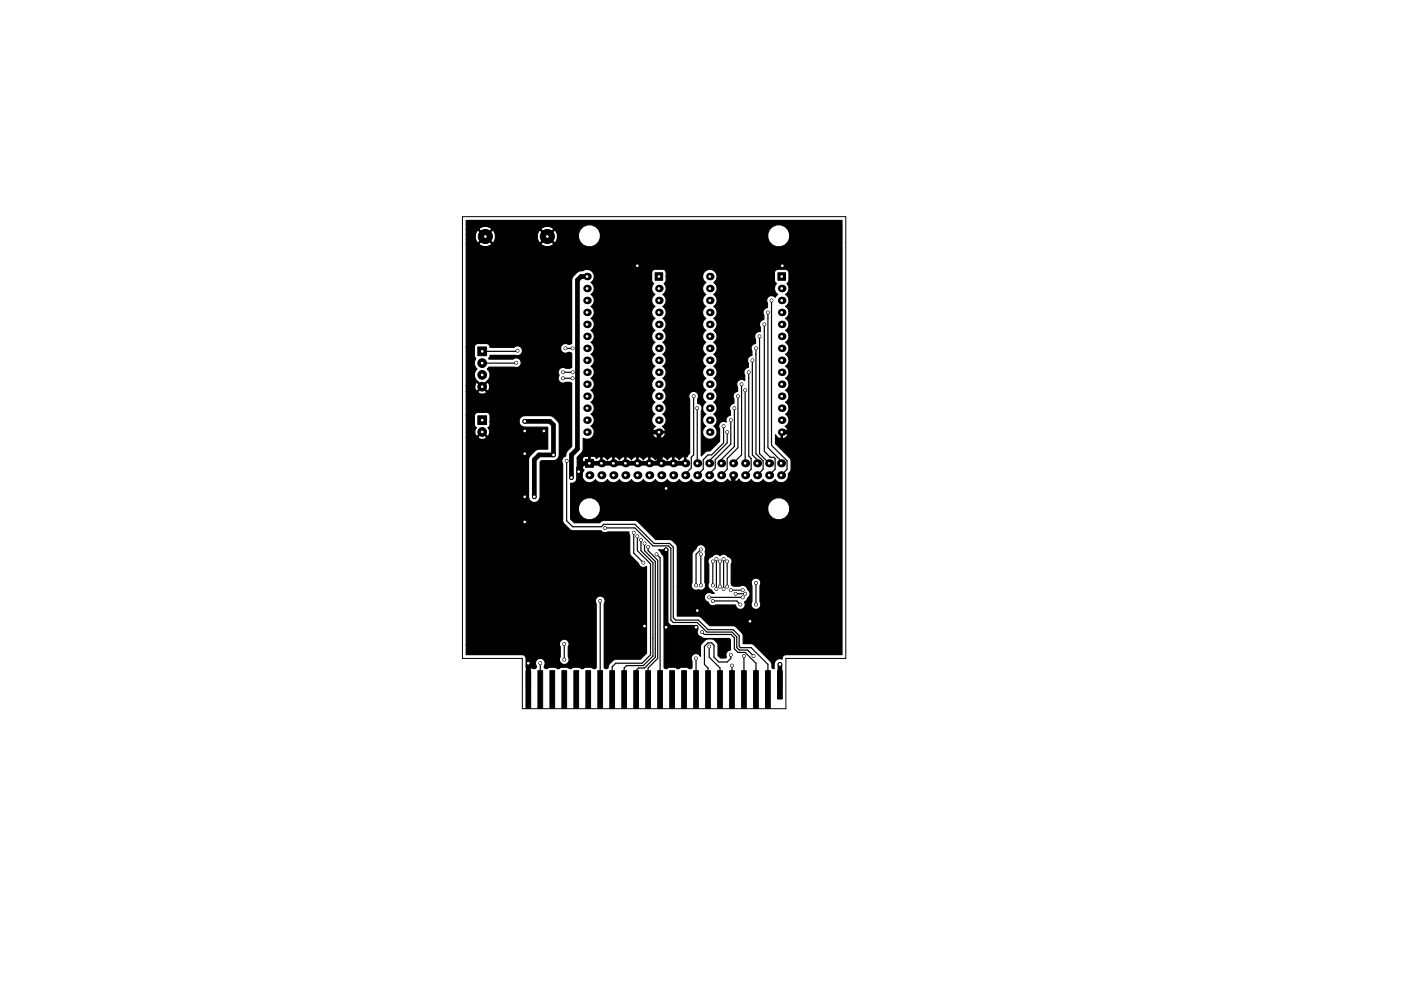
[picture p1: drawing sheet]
<svg xmlns="http://www.w3.org/2000/svg" width="297mm" height="210mm" viewBox="0 0 297 210" stroke-linecap="round" stroke-linejoin="round" font-family="sans-serif">
<path d="M98 46h81.3v93.7h-12.7v10.7h-55.9v-10.7h-12.7z" fill="none" stroke="#000" stroke-width=".21"/>
<g fill="#000" stroke="#000" stroke-width=".21">
<path d="M138.9 57.9h1.6v1.6h-1.6zM164.9 57.9h1.6v1.6h-1.6zM101.3 73.6h1.9v1.9h-1.9zM101.3 88.2h1.9v1.9h-1.9zM124.1 97.4h1.7v1.7h-1.7zM111.5 142.3h1v8h-1zM114.1 142.3h1v8h-1zM116.6 142.3h1v8h-1zM119.1 142.3h1v8h-1zM121.7 142.3h1v8h-1zM124.2 142.3h1v8h-1zM126.8 142.3h1v8h-1z"/>
<path d="M129.3 142.3h1v8h-1zM131.8 142.3h1v8h-1zM134.4 142.3h1v8h-1zM136.9 142.3h1v8h-1zM139.5 142.3h1v8h-1zM142 142.3h1v8h-1zM144.5 142.3h1v8h-1zM147.1 142.3h1v8h-1zM149.6 142.3h1v8h-1zM152.2 142.3h1v8h-1zM154.7 142.3h1v8h-1zM157.2 142.3h1v8h-1z"/>
<path d="M159.8 142.3h1v8h-1zM162.3 142.3h1v8h-1zM164.9 142.3h1v6h-1z"/>
<circle cx="102.9" cy="50.2" r="1.5"/>
<circle cx="116" cy="50.2" r="1.5"/>
<circle cx="135.1" cy="56.4" r=".4"/>
<circle cx="165.9" cy="56.4" r=".4"/>
<circle cx="102.2" cy="77" r=".92"/>
<circle cx="102.2" cy="79.5" r=".92"/>
<circle cx="109.5" cy="77" r=".3"/>
<circle cx="109.7" cy="74.4" r=".3"/>
<circle cx="119.4" cy="79" r=".3"/>
<circle cx="119.9" cy="73.9" r=".3"/>
<circle cx="121.4" cy="73.9" r=".3"/>
<circle cx="121.4" cy="79" r=".3"/>
<circle cx="158.8" cy="79" r=".3"/>
<circle cx="159.5" cy="76.4" r=".3"/>
<circle cx="160.3" cy="73.9" r=".3"/>
<circle cx="161" cy="71.4" r=".3"/>
<circle cx="162.1" cy="68.8" r=".3"/>
<circle cx="162.8" cy="66.3" r=".3"/>
<circle cx="163.6" cy="63.7" r=".3"/>
<circle cx="102.2" cy="91.6" r=".92"/>
<circle cx="102.2" cy="82" r=".92"/>
<circle cx="111.3" cy="96.3" r=".4"/>
<circle cx="111.3" cy="89.4" r=".4"/>
<circle cx="111.3" cy="91.4" r=".4"/>
<circle cx="115.3" cy="91.4" r=".4"/>
<circle cx="117.3" cy="96.5" r=".4"/>
<circle cx="119.4" cy="80.3" r=".3"/>
<circle cx="120.1" cy="97.8" r=".3"/>
<circle cx="121.4" cy="80.3" r=".3"/>
<circle cx="147.1" cy="84.1" r=".3"/>
<circle cx="147.8" cy="86.6" r=".3"/>
<circle cx="153.4" cy="90.4" r=".3"/>
<circle cx="154.2" cy="91.7" r=".3"/>
<circle cx="154.9" cy="89.1" r=".3"/>
<circle cx="155.7" cy="86.6" r=".3"/>
<circle cx="156.5" cy="84.1" r=".3"/>
<circle cx="157.2" cy="81.5" r=".3"/>
<circle cx="158" cy="82.8" r=".3"/>
<circle cx="111.3" cy="110.7" r=".4"/>
<circle cx="111.3" cy="105.4" r=".4"/>
<circle cx="113.3" cy="105.4" r=".4"/>
<circle cx="121.2" cy="101.3" r=".4"/>
<circle cx="122.7" cy="100.1" r=".4"/>
<circle cx="128.3" cy="112" r=".3"/>
<circle cx="134.4" cy="113" r=".3"/>
<circle cx="135.1" cy="113.8" r=".3"/>
<circle cx="135.9" cy="114.5" r=".3"/>
<circle cx="136.4" cy="119.4" r=".3"/>
<circle cx="136.7" cy="115.3" r=".3"/>
<circle cx="137.4" cy="116.1" r=".3"/>
<circle cx="139.2" cy="117.6" r=".3"/>
<circle cx="141.2" cy="103.6" r=".4"/>
<circle cx="141.2" cy="116.6" r=".4"/>
<circle cx="148.6" cy="116.6" r=".3"/>
<circle cx="148.6" cy="117.6" r=".3"/>
<circle cx="151.1" cy="119.1" r=".3"/>
<circle cx="151.9" cy="118.6" r=".3"/>
<circle cx="152.7" cy="119.1" r=".3"/>
<circle cx="153.4" cy="118.6" r=".3"/>
<circle cx="154.2" cy="119.1" r=".3"/>
<circle cx="119.6" cy="136.6" r=".3"/>
<circle cx="119.6" cy="139.9" r=".3"/>
<circle cx="127.3" cy="127.5" r=".3"/>
<circle cx="136.7" cy="132.8" r=".4"/>
<circle cx="141.2" cy="133.1" r=".4"/>
<circle cx="147.6" cy="133.1" r=".4"/>
<circle cx="147.6" cy="139.7" r=".3"/>
<circle cx="147.6" cy="124.2" r=".3"/>
<circle cx="147.8" cy="129.5" r=".4"/>
<circle cx="148.6" cy="124.2" r=".3"/>
<circle cx="148.8" cy="134.1" r=".3"/>
<circle cx="150.4" cy="137.2" r=".3"/>
<circle cx="150.4" cy="126.7" r=".3"/>
<circle cx="151.1" cy="127.5" r=".3"/>
<circle cx="151.1" cy="124.2" r=".3"/>
<circle cx="151.9" cy="125" r=".3"/>
<circle cx="152.7" cy="124.5" r=".3"/>
<circle cx="153.4" cy="125" r=".3"/>
<circle cx="154.2" cy="124.5" r=".3"/>
<circle cx="154.9" cy="138.9" r=".3"/>
<circle cx="154.9" cy="125.2" r=".3"/>
<circle cx="156" cy="126" r=".3"/>
<circle cx="157" cy="128.3" r=".3"/>
<circle cx="157.5" cy="126.7" r=".3"/>
<circle cx="157.5" cy="125.2" r=".3"/>
<circle cx="157.7" cy="139.2" r=".3"/>
<circle cx="158" cy="126" r=".3"/>
<circle cx="159" cy="131.8" r=".4"/>
<circle cx="159.8" cy="139.2" r=".3"/>
<circle cx="160.3" cy="128.3" r=".3"/>
<circle cx="160.3" cy="123.7" r=".3"/>
<circle cx="112" cy="140.7" r=".4"/>
<circle cx="114.6" cy="140.7" r=".3"/>
<circle cx="155.2" cy="141.2" r=".3"/>
<circle cx="165.4" cy="141" r=".4"/>
</g>
<g fill="#000">
<circle cx="124.5" cy="58.7" r=".8"/>
<circle cx="150.5" cy="58.7" r=".8"/>
<circle cx="124.5" cy="63.7" r=".8"/>
<circle cx="124.5" cy="61.2" r=".8"/>
<circle cx="124.5" cy="76.4" r=".8"/>
<circle cx="124.5" cy="66.3" r=".8"/>
<circle cx="124.5" cy="79" r=".8"/>
<circle cx="124.5" cy="71.4" r=".8"/>
<circle cx="124.5" cy="68.8" r=".8"/>
<circle cx="124.5" cy="73.9" r=".8"/>
<circle cx="139.7" cy="61.2" r=".8"/>
<circle cx="139.7" cy="63.7" r=".8"/>
<circle cx="139.7" cy="68.8" r=".8"/>
<circle cx="139.7" cy="71.4" r=".8"/>
<circle cx="139.7" cy="73.9" r=".8"/>
<circle cx="139.7" cy="76.4" r=".8"/>
<circle cx="139.7" cy="66.3" r=".8"/>
<circle cx="139.7" cy="79" r=".8"/>
<circle cx="150.5" cy="61.2" r=".8"/>
<circle cx="150.5" cy="63.7" r=".8"/>
<circle cx="150.5" cy="79" r=".8"/>
<circle cx="150.5" cy="76.4" r=".8"/>
<circle cx="150.5" cy="68.8" r=".8"/>
<circle cx="150.5" cy="73.9" r=".8"/>
<circle cx="150.5" cy="71.4" r=".8"/>
<circle cx="150.5" cy="66.3" r=".8"/>
<circle cx="165.7" cy="61.2" r=".8"/>
<circle cx="165.7" cy="66.3" r=".8"/>
<circle cx="165.7" cy="71.4" r=".8"/>
<circle cx="165.7" cy="63.7" r=".8"/>
<circle cx="165.7" cy="73.9" r=".8"/>
<circle cx="165.7" cy="76.4" r=".8"/>
<circle cx="165.7" cy="79" r=".8"/>
<circle cx="165.7" cy="68.8" r=".8"/>
<circle cx="124.5" cy="81.5" r=".8"/>
<circle cx="124.5" cy="91.7" r=".8"/>
<circle cx="124.5" cy="89.1" r=".8"/>
<circle cx="124.5" cy="86.6" r=".8"/>
<circle cx="124.5" cy="84.1" r=".8"/>
<circle cx="127.5" cy="98.3" r=".85"/>
<circle cx="130" cy="98.3" r=".85"/>
<circle cx="132.6" cy="98.3" r=".85"/>
<circle cx="135.1" cy="98.3" r=".85"/>
<circle cx="137.7" cy="98.3" r=".85"/>
<circle cx="139.7" cy="84.1" r=".8"/>
<circle cx="139.7" cy="86.6" r=".8"/>
<circle cx="139.7" cy="91.7" r=".8"/>
<circle cx="139.7" cy="89.1" r=".8"/>
<circle cx="139.7" cy="81.5" r=".8"/>
<circle cx="140.2" cy="98.3" r=".85"/>
<circle cx="142.7" cy="98.3" r=".85"/>
<circle cx="145.3" cy="98.3" r=".85"/>
<circle cx="147.8" cy="98.3" r=".85"/>
<circle cx="150.4" cy="98.3" r=".85"/>
<circle cx="150.5" cy="89.1" r=".8"/>
<circle cx="150.5" cy="84.1" r=".8"/>
<circle cx="150.5" cy="81.5" r=".8"/>
<circle cx="150.5" cy="91.7" r=".8"/>
<circle cx="150.5" cy="86.6" r=".8"/>
<circle cx="152.9" cy="98.3" r=".85"/>
<circle cx="155.4" cy="98.3" r=".85"/>
<circle cx="158" cy="98.3" r=".85"/>
<circle cx="160.5" cy="98.3" r=".85"/>
<circle cx="163.1" cy="98.3" r=".85"/>
<circle cx="165.6" cy="98.3" r=".85"/>
<circle cx="165.7" cy="81.5" r=".8"/>
<circle cx="165.7" cy="91.7" r=".8"/>
<circle cx="165.7" cy="84.1" r=".8"/>
<circle cx="165.7" cy="89.1" r=".8"/>
<circle cx="165.7" cy="86.6" r=".8"/>
<circle cx="125" cy="100.8" r=".85"/>
<circle cx="127.5" cy="100.8" r=".85"/>
<circle cx="130" cy="100.8" r=".85"/>
<circle cx="132.6" cy="100.8" r=".85"/>
<circle cx="135.1" cy="100.8" r=".85"/>
<circle cx="137.7" cy="100.8" r=".85"/>
<circle cx="140.2" cy="100.8" r=".85"/>
<circle cx="142.7" cy="100.8" r=".85"/>
<circle cx="145.3" cy="100.8" r=".85"/>
<circle cx="147.8" cy="100.8" r=".85"/>
<circle cx="150.4" cy="100.8" r=".85"/>
<circle cx="152.9" cy="100.8" r=".85"/>
<circle cx="155.4" cy="100.8" r=".85"/>
<circle cx="158" cy="100.8" r=".85"/>
<circle cx="160.5" cy="100.8" r=".85"/>
<circle cx="163.1" cy="100.8" r=".85"/>
<circle cx="165.6" cy="100.8" r=".85"/>
</g>
<path d="M124.5 58.7h-1.3l-.8 .7v35.8l-1.2 1.3v4.8M135.1 56.4v34.8l.5 .5h4.1v6.1l.5 .5M165.9 56.4h10.4l1 1v71.1l-3.3 3.3h-23.9l-2.3-2.3M167.4 56.4l.5 .5v34.3l-.5 .5h-1.7M111.3 89.4h5.3l.7 .8v6.3h-3l-1 1v7.9M115.3 91.4h-4v14M145.3 98.3h-21.6l-1 1v3.1l1.3 1.2h30.9l.5-.5v-2.3M111.3 110.7l.7 .8v34.8M141.2 116.6v16.5h6.4M112 125.2h17l7.7 7.6M165.4 141v4.3" fill="none" stroke="#000" stroke-width="1"/>
<g fill="none" stroke="#000" stroke-width=".25">
<path d="M109.5 77h-7.3M109.7 74.4l-.1 .1h-7.4M119.4 79h2M119.9 73.9h1.5M158.7 79v17.8l.6 .5v2.3l-1.3 1.2M159.5 76.4v20.1l1 1v.8M160.3 73.9v22.4l1.5 1.5v1.8l-1.3 1.2M161 71.4v24.9l2.1 2M162.1 68.8v27l1.2 1.2h.8l.2 .3v2.3l-1.2 1.2M162.8 66.3v28.7l2.8 2.8v.5M163.6 63.7v30.8l3.3 3.3v1.8l-1.3 1.2M119.4 80.3h2"/>
<path d="M120.1 97.8v12.7l1.3 1.3h6.1l.5-.6h6.6l4.1 4.1h3.3l.7 .8v15l.6 .5h4.8l2 2h5.3l1.3 1.3v2.3l.3 .2h2.3l3.5 3.6v5.3M147.1 84.1v12.4l-.5 .5v2.3l-1.3 1.3v.2M147.8 86.6v11.7M153.4 90.4v3.6l-2.5 2.5h-.8l-1 1v2.1l-1.3 1.2M154.2 91.7v2.3l-3.8 3.8v.5M154.9 89.1v5.1l-3.3 3.3v1.8l-1.2 1.3v.2M155.7 86.6v8.1l-2.8 2.8v.8M156.5 84.1v10.9l-2.3 2.3v2.3l-1.3 1.2M157.2 81.5v15l-1.8 1.8M158 82.8v15.5M128.3 112h6.3l3.8 3.8h3.3l.5 .5v15.3l.5 .5h5.1l2.1 2h5.3l1 1v2.3l.5 .5h1.8l1.3 1.3M134.4 113v4.3l2 2.1"/>
<path d="M135.1 113.8v3l2.8 2.8v19.3l-1.8 1.8h-5.5l-.8 .8v4.8l.2-.3M135.9 114.5v2.3l2.5 2.6v19.8l-2 2h-3.6l-.5 .5v4.6M136.7 115.3v1.5l2.2 2.3v20.3l-2.2 2.3h-1.3l-.5 .5v4.1M137.4 116.1v.7l2 2.1v20.8l-2 2v4.6M139.2 117.6l.8 .8v27.9M148.6 117.6v6.6M148.6 116.6l-1 1v6.6M151.1 119.1v5.1M151.9 118.6v6.4M152.7 119.1v5.4M153.4 118.6v6.4M154.2 119.1v5.4"/>
<path d="M119.6 136.6v3.3M127.3 127.5v18.8M147.6 139.7v6.6M148.8 134.1l.6 .5h5.6l.7 .7v2.4l.8 .7h1.5l2.3 2.3v5.6M150.4 137.2v2.2l2.3 2.3v4.6M150.4 126.7h7.1M151.1 127.5h5.1l.8 .8M154.9 138.9v.8l-.7 .8h-1.8l-1-1.1v-2.5l-.5-.5h-.8l-.7 .8v3.8l.7 .7v4.6M154.9 125.2h2.6M156 126h2M157.7 139.2v7.1M160.3 123.7v4.6"/>
<path d="M114.6 140.7v5.6M155.2 141.2v5.1"/>
</g>
<path d="M139.6 116.7h1.8v14.9a1.76 1.76 0 0 0 1.3 1.3h4.8l.5 .6a1.11 1.11 0 0 0 .7 1.7l.7 .3h5.2l.3 .2v2.2a1.01 1.01 0 0 0-.9 1.5l-.2 .2h-1l-.6-.5v-2.2a1.91 1.91 0 0 0-1.9-1.4 1.91 1.91 0 0 0-1.8 1.7v2a1.04 1.04 0 0 0-1.5-.4 1.04 1.04 0 0 0-.3 1.5v1.4l-.2 .2-.4-.1a2 2 0 0 0-2.1 0h-.5a2 2 0 0 0-2 0l-.5 .1-.2-.2v-23.3l-.7-1.4zM98.8 46.8h79.7v92.1l-12.2 .1a.83 .83 0 0 0-.5 .8 1.23 1.23 0 0 0-1.7 1.2v.9h-.2l-.2-.2v-.7l-.3-.6-3.5-3.6-.6-.2h-1.7l-.1-2.1-1.7-1.7-5.3-.1-2.1-1.9-4.8-.1v-3.8h5.7l.2 .4 .6 .4 .2 .4a1.04 1.04 0 0 0 1.4 .3h4.2a1.04 1.04 0 0 0 1.5 .8 1.04 1.04 0 0 0 .4-1.5 .95 .95 0 0 0 .7-.8 1.09 1.09 0 0 0 0-1.9 1.04 1.04 0 0 0-1.6-.6h-1.4l-.3-.2-.1-.3h4.1l.2 .4v3.4a1.04 1.04 0 0 0 .9 1.6 1.04 1.04 0 0 0 .8-1.6v-3.4a1.05 1.05 0 0 0-.6-1.6 1.05 1.05 0 0 0-1.3 1.2h-4.1l-.1-4.2a1.1 1.1 0 0 0-.7-1.7 1.02 1.02 0 0 0-1.6-.1 1.09 1.09 0 0 0-1.8 .2 1.04 1.04 0 0 0-.6 1.6v3.9a1.04 1.04 0 0 0 .6 1.6l.1 .3 .4 .4h-.4a1.04 1.04 0 0 0-1.2 0 1.04 1.04 0 0 0-.5 1h-5.7v-2.5h2.9l.2 .4a1.02 1.02 0 0 0 1.4 .3 1.04 1.04 0 0 0 1.3-.2 1.04 1.04 0 0 0 0-1.3v-5.4l.2-.4-.1-.7 .1-.3a1.04 1.04 0 0 0-.8-1.2 1.04 1.04 0 0 0-1.2 .8l-.6 .6-.3 .6v6l-.2 .8h-2.9l-.1-8.7a2.37 2.37 0 0 0-1.5-1.2h-3l-3.8-3.9-.6-.2h-6.6l-.3 .1-.5 .4h-5.4l-.8-.8v-1.7h1.6a2.37 2.37 0 0 0 2.4 1.9 2.37 2.37 0 0 0 2.3-1.9h35.5l.3 .9a2.37 2.37 0 0 0 4 0 2.37 2.37 0 0 0-1.5-3.7 2.37 2.37 0 0 0-2.8 2.8h-35.5v-.9a2.37 2.37 0 0 0-2.8-1.9 2.37 2.37 0 0 0-1.9 2.8h-1.6v-5.9a1.31 1.31 0 0 0 1.4-1.7l1 .1a1.56 1.56 0 0 0 1.1 1.5 1.56 1.56 0 0 0 1.7-.7 1.51 1.51 0 0 0 2.6 0 1.51 1.51 0 0 0 2.5 0 1.51 1.51 0 0 0 2.6 0 1.51 1.51 0 0 0 2.5 0 1.51 1.51 0 0 0 2.5 0 1.51 1.51 0 0 0 2.6 0 1.51 1.51 0 0 0 2.5 0 1.51 1.51 0 0 0 2.6 0 1.51 1.51 0 0 0 2.5 0 1.51 1.51 0 0 0 2.5 0 1.51 1.51 0 0 0 2.6 0l.5 .4 .4 .2 .2-.1v-1.5h.3v1.5l.2 .1 .4-.2 .5-.4 .2 .3a1.54 1.54 0 0 0 2.4-.3 1.51 1.51 0 0 0 2.5 0 1.51 1.51 0 0 0 2.5 0 1.55 1.55 0 0 0 1.9 .6 1.55 1.55 0 0 0 .9-1.8l.6-.6v-.3v-2.1l-3.3-3.4v-1.9a1 1 0 0 0 1.2 .8v-1.2h.3v1.2l.2 .1a1.02 1.02 0 0 0 .9-1.3h-1.4v-.3l1.4 .1 .1-.3-.1-.3-.5-.5 .3-.3a1.49 1.49 0 0 0-.2-2.3 1.47 1.47 0 0 0 0-2.6 1.47 1.47 0 0 0 0-2.5 1.47 1.47 0 0 0 0-2.5 1.47 1.47 0 0 0 0-2.6 1.47 1.47 0 0 0 0-2.5 1.47 1.47 0 0 0 0-2.6 1.47 1.47 0 0 0 0-2.5 1.47 1.47 0 0 0 0-2.5 1.47 1.47 0 0 0 0-2.6 1.47 1.47 0 0 0 0-2.5 1.48 1.48 0 0 0 .2-2.4l.4-.3 .1-.3v-1.6a.74 .74 0 0 0-.8-.8l-1.8 .1-.4 .4-.1 1.9 .4 .6-.3 .5a1.46 1.46 0 0 0 .6 1.9l-.5 .6a1.04 1.04 0 0 0-1.5-.2 1.04 1.04 0 0 0-.2 1.4v1h-.1a1.04 1.04 0 0 0-.6 1.6v.9h-.2a1.04 1.04 0 0 0-.6 1.6v.9h-.4a1.04 1.04 0 0 0-.6 1.7v.9h-.1a1.04 1.04 0 0 0-.7 1.6v.9h-.1a1.04 1.04 0 0 0-.6 1.6v1h-.2a1.04 1.04 0 0 0-.6 1.6v1.1h-.1a1.04 1.04 0 0 0-1.3 .1 1.04 1.04 0 0 0-.1 1.3v.9h-.1a1.04 1.04 0 0 0-.7 1.7v.9h-.1a1.04 1.04 0 0 0-.6 1.6v.9h-.2a1.02 1.02 0 0 0-.7 1.4 1.04 1.04 0 0 0-1.3 .2 1.04 1.04 0 0 0-.1 1.3v2.6l-2.1 2.1h-.7l-1.1 1v-9.5a1.03 1.03 0 0 0-.8-1.6v-.9a1.05 1.05 0 0 0-.8-1.7 1.05 1.05 0 0 0-.9 1.7v11.5l-.5 .7-.3 .1v1.4h-21.8l-.1 .2v.7l.3 .4-.3 .5-.1 .6h-1v-3.5h1.1v.7l.1 .2h1.2v-1.2h.3v1.2h2.3v-1.2h.2v1.2h2.3v-1.2h.3v1.2h2.3v-1.2h.2v1.2h2.3v-1.2h.3v1.2h2.2v-1.2h.3v1.2h2.3v-1.2h.2v1.2h2.3v-1.2h.3v1.2h2.3v-1.2l-.3-.1-.4 .1-.5 .6-.5-.6-.4-.1-.2 .1-.5-.1-.4 .1-.5 .6-.5-.6-.4-.1-.3 .1-.4-.1-.5 .1-.5 .6-.5-.6-.4-.1-.2 .1-.5-.1-.4 .1-.5 .6-.5-.6-.4-.1-.2 .1-.5-.1-.4 .1-.5 .6-.5-.6-.5-.1-.2 .1-.5-.1-.4 .1-.5 .6-.5-.6-.4-.1-.2 .1-.5-.1-.4 .1-.5 .6-.5-.6-.4-.1-.3 .1a.86 .86 0 0 0-1.2 .3l-.5-.5h-.6l-.2 .2-1.1-.2-.5 .5h-1.1v-.3l1.2-1.3 .1-2.7a1.51 1.51 0 0 0 2.2-1h12.4l.5 .8 .6 .3 .2-.1v-1.2h.2v1.2a.95 .95 0 0 0 1.2-1.2h-2.6l-.1 .2h-12.4v-.9l-.6-.7 .3-.2a1.49 1.49 0 0 0-.3-2.3 1.47 1.47 0 0 0 0-2.6 1.47 1.47 0 0 0 0-2.5 1.47 1.47 0 0 0 0-2.5 1.47 1.47 0 0 0 0-2.6 1.47 1.47 0 0 0 0-2.5 1.47 1.47 0 0 0 0-2.6 1.47 1.47 0 0 0 0-2.5 1.47 1.47 0 0 0 0-2.5 1.47 1.47 0 0 0 0-2.6 1.47 1.47 0 0 0 0-2.5l.6-.7 .1-.6h12.1l.2 .6 .6 .7-.3 .2a1.49 1.49 0 0 0 .3 2.3 1.47 1.47 0 0 0 0 2.6 1.47 1.47 0 0 0 0 2.5 1.47 1.47 0 0 0 0 2.5 1.47 1.47 0 0 0 0 2.6 1.47 1.47 0 0 0 0 2.5 1.47 1.47 0 0 0 0 2.6 1.47 1.47 0 0 0 0 2.5 1.47 1.47 0 0 0 0 2.5 1.47 1.47 0 0 0 0 2.6 1.48 1.48 0 0 0 .1 2.6l-.5 .5-.2 .3 .1 .3h2.6l.1-.3-.2-.3-.5-.5 .4-.3a1.49 1.49 0 0 0-.3-2.3 1.47 1.47 0 0 0 0-2.6 1.47 1.47 0 0 0 0-2.5 1.47 1.47 0 0 0 0-2.5 1.47 1.47 0 0 0 0-2.6 1.47 1.47 0 0 0 0-2.5 1.47 1.47 0 0 0 0-2.6 1.47 1.47 0 0 0 0-2.5 1.47 1.47 0 0 0 0-2.5 1.47 1.47 0 0 0 0-2.6 1.47 1.47 0 0 0 0-2.5 1.48 1.48 0 0 0 .3-2.4l.4-.3v-1.1h7.7l.2 .6 .6 .6a1.47 1.47 0 0 0 0 2.6 1.47 1.47 0 0 0 0 2.5 1.47 1.47 0 0 0 0 2.6 1.47 1.47 0 0 0 0 2.5 1.47 1.47 0 0 0 0 2.5 1.47 1.47 0 0 0 0 2.6 1.47 1.47 0 0 0 0 2.5 1.47 1.47 0 0 0 0 2.6 1.47 1.47 0 0 0 0 2.5 1.47 1.47 0 0 0 0 2.5 1.47 1.47 0 0 0 0 2.6 1.47 1.47 0 0 0 0 2.5 1.52 1.52 0 0 0-.4 2.3 1.52 1.52 0 0 0 2.3 0 1.52 1.52 0 0 0-.3-2.3 1.47 1.47 0 0 0 0-2.5 1.47 1.47 0 0 0 0-2.6 1.47 1.47 0 0 0 0-2.5 1.47 1.47 0 0 0 0-2.5 1.47 1.47 0 0 0 0-2.6 1.47 1.47 0 0 0 0-2.5 1.47 1.47 0 0 0 0-2.6 1.47 1.47 0 0 0 0-2.5 1.47 1.47 0 0 0 0-2.5 1.47 1.47 0 0 0 0-2.6 1.47 1.47 0 0 0 0-2.5 1.47 1.47 0 0 0 0-2.6 1.54 1.54 0 0 0-.1-2.6 1.54 1.54 0 0 0-2.3 1.4h-7.7v-.8a.74 .74 0 0 0-.7-.8l-1.9 .1-.4 .4v1.9l.4 .6-.3 .5-.2 .6h-12.1l-.1-.6-.6-.7 .3-.2a1.53 1.53 0 0 0 0-2 1.53 1.53 0 0 0-2-.3 2.44 2.44 0 0 0-2.4 2v13.5l-.7 .2a1.04 1.04 0 0 0-1.7 .8 1.04 1.04 0 0 0 1.7 .9l.7 .1v3.1l-.4 .1h-.8a1.09 1.09 0 0 0-1.4 .2 1.09 1.09 0 0 0-.1 1.4 1.04 1.04 0 0 0 .1 1.3 1.04 1.04 0 0 0 1.4 .1h.8l.4 .2v13.4l-1.2 1.3-.1 .8a1.04 1.04 0 0 0-.6 1.6l.1 12.4 1.7 1.7 6.3 .1 .3 .3a1.03 1.03 0 0 0 1.2 0h4.4l.2 .7 .1 4.1 1.8 1.9a1.03 1.03 0 0 0 1.7 .6v18.4l-1.3 1.3h-5.6a2.15 2.15 0 0 0-1.3 1.8l-.2 .2h-.4l-.2-.2v-13.6a1.04 1.04 0 0 0-.8-1.6 1.04 1.04 0 0 0-.9 1.6v13.6l-.2 .2h-.4l-.3-.3a2.17 2.17 0 0 0-1.8 .2l-.4 .1-.3-.3a2.17 2.17 0 0 0-1.8 .2l-.5 .1-.3-.3a2.17 2.17 0 0 0-1.8 .2l-.4 .1-.3-.3a2.17 2.17 0 0 0-1.8 .2l-.5 .1-.2-.2v-.4a1.05 1.05 0 0 0-.9-1.6 1.05 1.05 0 0 0-.8 1.6v.4l-.2 .2h-.5a.56 .56 0 0 0-.9-.1l-.6-.1v-2a.8 .8 0 0 0-.8-.8h-11.9v-2.1h19.8l.2 .4v2.1a1.04 1.04 0 0 0 .8 1.7 1.04 1.04 0 0 0 .9-1.7v-2.1a1.05 1.05 0 0 0-.7-1.6 1.05 1.05 0 0 0-1.2 1.2h-19.8v-44.1h2.5l.1 .3a1.18 1.18 0 0 0 1.8-.3l-1-.9-.9 .9h-2.5v-4.5h1.8v1.9l.2 .5 .2 .2a1.13 1.13 0 0 0 .1 1.8l1.1-1.1 1.1 1.1a1.12 1.12 0 0 0 .1-1.8l.4-.4 .1-1h6.1l.4 .9 .4 .2 5.3 .1v4.7l-2.3 .1a3.3 3.3 0 0 0-1.7 2.1l.1 8.4a1.23 1.23 0 0 0 1.3 .7 1.23 1.23 0 0 0 1-1.2v-7.4l.3-.3 3-.1 .7-.6 .1-6.8a2.58 2.58 0 0 0-2-2h-5.3l-.9 .3-.4 .9h-6.1v-1.2l-.2-.5-.5-.2h-1.9a.74 .74 0 0 0-.7 .7h-1.8v-5.1h2.5l.1 .3a1.18 1.18 0 0 0 1.8-.3l-1-.9-.9 .9h-2.5v-1.3h1.9v.6l.2 .5 .2 .1 1-1h.3l.9 1 .3-.1a1.18 1.18 0 0 0-.3-1.8l-.9 .9h-.3l-1-.9-.2 .1-.2 .6h-1.9v-8.2h1.8v1.9l.3 .6a1.61 1.61 0 0 0 .2 2.2 1.64 1.64 0 0 0 .2 2.7l.9 .9 .9-.9a1.65 1.65 0 0 0 .2-2.7l.4-.4 5.6 .1a1.04 1.04 0 0 0 1.2-1.3 1.04 1.04 0 0 0-1.7-.5h-5.1l-.1-.1 .3-.7h5.5a1.03 1.03 0 0 0 1.3-1.2 1.03 1.03 0 0 0-1.7-.5l-5.1-.1a.74 .74 0 0 0-.7-.7h-1.9l-.5 .2-.2 .5h-1.8v-21.9h2.8a1.66 1.66 0 0 0 2.6 0h10.5l.2 .3a1.78 1.78 0 0 0 2.5-.3l-1.4-1.3-1.3 1.3h-10.5l-1.3-1.3-1.3 1.3h-2.8v-1.9h2v.8l.3 .8 .3 .1 1.3-1.3h.4l1.3 1.3 .3-.1 .3-.8v-.8h8.9v.8l.3 .8 .3 .1 1.4-1.3h.3l1.4 1.3 .3-.1 .3-.9h4.4a2.37 2.37 0 0 0 2.4 1.9 2.37 2.37 0 0 0 2.3-1.9h35.5l.3 .8a2.37 2.37 0 0 0 4 .1 2.37 2.37 0 0 0-1.5-3.7 2.37 2.37 0 0 0-2.8 2.8h-35.5v-.9a2.37 2.37 0 0 0-2.8-1.9 2.37 2.37 0 0 0-1.9 2.8h-4.4v-.8l-.3-.7-.3-.2-1.4 1.4h-.3l-1.4-1.4-.3 .2-.3 .8h-8.9l-.3-.8-.3-.2-1.3 1.4h-.4l-1.3-1.4-.3 .2-.3 .8h-2v-1.1h2.8l1.3 1.3 1.3-1.3h10.5l1.3 1.3 1.4-1.3a1.66 1.66 0 0 0-2.7 0h-10.5l-.1-.4a1.78 1.78 0 0 0-2.5 .4h-2.8z" fill="#000" stroke="#000" stroke-width=".25"/>
<g fill="#fff" stroke="#fff" stroke-width=".21">
<circle cx="111.3" cy="89.4" r=".17"/>
<circle cx="165.4" cy="141" r=".17"/>
<circle cx="113.3" cy="105.4" r=".17"/>
<circle cx="117.3" cy="96.5" r=".17"/>
<circle cx="121.2" cy="101.3" r=".17"/>
<circle cx="159" cy="131.8" r=".17"/>
<circle cx="165.9" cy="56.4" r=".17"/>
<circle cx="141.2" cy="103.6" r=".17"/>
<circle cx="141.2" cy="116.6" r=".17"/>
<circle cx="136.7" cy="132.8" r=".17"/>
<circle cx="141.2" cy="133.1" r=".17"/>
<circle cx="147.6" cy="133.1" r=".17"/>
<circle cx="147.8" cy="129.5" r=".17"/>
<circle cx="111.3" cy="110.7" r=".17"/>
<circle cx="135.1" cy="56.4" r=".17"/>
<circle cx="122.7" cy="100.1" r=".17"/>
<circle cx="112" cy="140.7" r=".17"/>
<circle cx="111.3" cy="96.3" r=".17"/>
<circle cx="115.3" cy="91.4" r=".17"/>
<circle cx="111.3" cy="91.4" r=".17"/>
<circle cx="111.3" cy="105.4" r=".17"/>
<circle cx="109.5" cy="77" r=".17"/>
<circle cx="109.7" cy="74.4" r=".17"/>
<circle cx="139.2" cy="117.6" r=".17"/>
<circle cx="147.1" cy="84.1" r=".17"/>
<circle cx="119.6" cy="136.6" r=".17"/>
<circle cx="119.6" cy="139.9" r=".17"/>
<circle cx="147.8" cy="86.6" r=".17"/>
<circle cx="153.4" cy="90.4" r=".17"/>
<circle cx="157" cy="128.3" r=".17"/>
<circle cx="154.2" cy="91.7" r=".17"/>
<circle cx="151.1" cy="127.5" r=".17"/>
<circle cx="151.1" cy="124.2" r=".17"/>
<circle cx="151.1" cy="119.1" r=".17"/>
<circle cx="154.9" cy="89.1" r=".17"/>
<circle cx="151.9" cy="118.6" r=".17"/>
<circle cx="151.9" cy="125" r=".17"/>
<circle cx="155.7" cy="86.6" r=".17"/>
<circle cx="152.7" cy="124.5" r=".17"/>
<circle cx="152.7" cy="119.1" r=".17"/>
<circle cx="156.5" cy="84.1" r=".17"/>
<circle cx="153.4" cy="125" r=".17"/>
<circle cx="153.4" cy="118.6" r=".17"/>
<circle cx="157.2" cy="81.5" r=".17"/>
<circle cx="154.2" cy="124.5" r=".17"/>
<circle cx="154.2" cy="119.1" r=".17"/>
<circle cx="158" cy="82.8" r=".17"/>
<circle cx="158.7" cy="79" r=".17"/>
<circle cx="159.5" cy="76.4" r=".17"/>
<circle cx="160.3" cy="73.9" r=".17"/>
<circle cx="161" cy="71.4" r=".17"/>
<circle cx="162.1" cy="68.8" r=".17"/>
<circle cx="162.8" cy="66.3" r=".17"/>
<circle cx="163.6" cy="63.7" r=".17"/>
<circle cx="119.9" cy="73.9" r=".17"/>
<circle cx="121.4" cy="73.9" r=".17"/>
<circle cx="119.4" cy="80.3" r=".17"/>
<circle cx="121.4" cy="80.3" r=".17"/>
<circle cx="119.4" cy="79" r=".17"/>
<circle cx="121.4" cy="79" r=".17"/>
<circle cx="154.9" cy="138.9" r=".17"/>
<circle cx="160.3" cy="128.3" r=".17"/>
<circle cx="160.3" cy="123.7" r=".17"/>
<circle cx="157.5" cy="125.2" r=".17"/>
<circle cx="154.9" cy="125.2" r=".17"/>
<circle cx="158" cy="126" r=".17"/>
<circle cx="156" cy="126" r=".17"/>
<circle cx="155.2" cy="141.2" r=".17"/>
<circle cx="157.5" cy="126.7" r=".17"/>
<circle cx="150.4" cy="126.7" r=".17"/>
<circle cx="150.4" cy="137.2" r=".17"/>
<circle cx="148.6" cy="124.2" r=".17"/>
<circle cx="147.6" cy="139.7" r=".17"/>
<circle cx="148.6" cy="117.6" r=".17"/>
<circle cx="137.4" cy="116.1" r=".17"/>
<circle cx="136.7" cy="115.3" r=".17"/>
<circle cx="135.9" cy="114.5" r=".17"/>
<circle cx="135.1" cy="113.8" r=".17"/>
<circle cx="147.6" cy="124.2" r=".17"/>
<circle cx="148.6" cy="116.6" r=".17"/>
<circle cx="148.8" cy="134.1" r=".17"/>
<circle cx="134.4" cy="113" r=".17"/>
<circle cx="136.4" cy="119.4" r=".17"/>
<circle cx="114.6" cy="140.7" r=".17"/>
<circle cx="120.1" cy="97.8" r=".17"/>
<circle cx="159.8" cy="139.2" r=".17"/>
<circle cx="128.3" cy="112" r=".17"/>
<circle cx="157.7" cy="139.2" r=".17"/>
<circle cx="127.3" cy="127.5" r=".17"/>
<circle cx="102.9" cy="50.2" r=".17"/>
<circle cx="116" cy="50.2" r=".17"/>
<circle cx="102.2" cy="89.1" r=".17"/>
<circle cx="102.2" cy="91.6" r=".17"/>
<circle cx="125" cy="98.3" r=".17"/>
<circle cx="125" cy="100.8" r=".17"/>
<circle cx="127.5" cy="98.3" r=".17"/>
<circle cx="127.5" cy="100.8" r=".17"/>
<circle cx="130" cy="98.3" r=".17"/>
<circle cx="130" cy="100.8" r=".17"/>
<circle cx="132.6" cy="98.3" r=".17"/>
<circle cx="132.6" cy="100.8" r=".17"/>
<circle cx="135.1" cy="98.3" r=".17"/>
<circle cx="135.1" cy="100.8" r=".17"/>
<circle cx="137.7" cy="98.3" r=".17"/>
<circle cx="137.7" cy="100.8" r=".17"/>
<circle cx="140.2" cy="98.3" r=".17"/>
<circle cx="140.2" cy="100.8" r=".17"/>
<circle cx="142.7" cy="98.3" r=".17"/>
<circle cx="142.7" cy="100.8" r=".17"/>
<circle cx="145.3" cy="98.3" r=".17"/>
<circle cx="145.3" cy="100.8" r=".17"/>
<circle cx="147.8" cy="98.3" r=".17"/>
<circle cx="147.8" cy="100.8" r=".17"/>
<circle cx="150.4" cy="98.3" r=".17"/>
<circle cx="150.4" cy="100.8" r=".17"/>
<circle cx="152.9" cy="98.3" r=".17"/>
<circle cx="152.9" cy="100.8" r=".17"/>
<circle cx="155.4" cy="98.3" r=".17"/>
<circle cx="155.4" cy="100.8" r=".17"/>
<circle cx="158" cy="98.3" r=".17"/>
<circle cx="158" cy="100.8" r=".17"/>
<circle cx="160.5" cy="98.3" r=".17"/>
<circle cx="160.5" cy="100.8" r=".17"/>
<circle cx="163.1" cy="98.3" r=".17"/>
<circle cx="163.1" cy="100.8" r=".17"/>
<circle cx="165.6" cy="98.3" r=".17"/>
<circle cx="165.6" cy="100.8" r=".17"/>
<circle cx="102.2" cy="74.5" r=".17"/>
<circle cx="102.2" cy="77" r=".17"/>
<circle cx="102.2" cy="79.5" r=".17"/>
<circle cx="102.2" cy="82" r=".17"/>
<circle cx="125" cy="107.9" r=".17"/>
<circle cx="165.1" cy="107.9" r=".17"/>
<circle cx="125" cy="50" r=".17"/>
<circle cx="165.1" cy="50" r=".17"/>
<circle cx="139.7" cy="58.7" r=".17"/>
<circle cx="124.5" cy="91.7" r=".17"/>
<circle cx="139.7" cy="61.2" r=".17"/>
<circle cx="124.5" cy="89.1" r=".17"/>
<circle cx="139.7" cy="63.7" r=".17"/>
<circle cx="124.5" cy="86.6" r=".17"/>
<circle cx="139.7" cy="66.3" r=".17"/>
<circle cx="124.5" cy="84.1" r=".17"/>
<circle cx="139.7" cy="68.8" r=".17"/>
<circle cx="124.5" cy="81.5" r=".17"/>
<circle cx="139.7" cy="71.4" r=".17"/>
<circle cx="124.5" cy="79" r=".17"/>
<circle cx="139.7" cy="73.9" r=".17"/>
<circle cx="124.5" cy="76.4" r=".17"/>
<circle cx="139.7" cy="76.4" r=".17"/>
<circle cx="124.5" cy="73.9" r=".17"/>
<circle cx="139.7" cy="79" r=".17"/>
<circle cx="124.5" cy="71.4" r=".17"/>
<circle cx="139.7" cy="81.5" r=".17"/>
<circle cx="124.5" cy="68.8" r=".17"/>
<circle cx="139.7" cy="84.1" r=".17"/>
<circle cx="124.5" cy="66.3" r=".17"/>
<circle cx="139.7" cy="86.6" r=".17"/>
<circle cx="124.5" cy="63.7" r=".17"/>
<circle cx="139.7" cy="89.1" r=".17"/>
<circle cx="124.5" cy="61.2" r=".17"/>
<circle cx="139.7" cy="91.7" r=".17"/>
<circle cx="124.5" cy="58.7" r=".17"/>
<circle cx="165.7" cy="58.7" r=".17"/>
<circle cx="150.5" cy="91.7" r=".17"/>
<circle cx="165.7" cy="61.2" r=".17"/>
<circle cx="150.5" cy="89.1" r=".17"/>
<circle cx="165.7" cy="63.7" r=".17"/>
<circle cx="150.5" cy="86.6" r=".17"/>
<circle cx="165.7" cy="66.3" r=".17"/>
<circle cx="150.5" cy="84.1" r=".17"/>
<circle cx="165.7" cy="68.8" r=".17"/>
<circle cx="150.5" cy="81.5" r=".17"/>
<circle cx="165.7" cy="71.4" r=".17"/>
<circle cx="150.5" cy="79" r=".17"/>
<circle cx="165.7" cy="73.9" r=".17"/>
<circle cx="150.5" cy="76.4" r=".17"/>
<circle cx="165.7" cy="76.4" r=".17"/>
<circle cx="150.5" cy="73.9" r=".17"/>
<circle cx="165.7" cy="79" r=".17"/>
<circle cx="150.5" cy="71.4" r=".17"/>
<circle cx="165.7" cy="81.5" r=".17"/>
<circle cx="150.5" cy="68.8" r=".17"/>
<circle cx="165.7" cy="84.1" r=".17"/>
<circle cx="150.5" cy="66.3" r=".17"/>
<circle cx="165.7" cy="86.6" r=".17"/>
<circle cx="150.5" cy="63.7" r=".17"/>
<circle cx="165.7" cy="89.1" r=".17"/>
<circle cx="150.5" cy="61.2" r=".17"/>
<circle cx="165.7" cy="91.7" r=".17"/>
<circle cx="150.5" cy="58.7" r=".17"/>
</g>
</svg>
